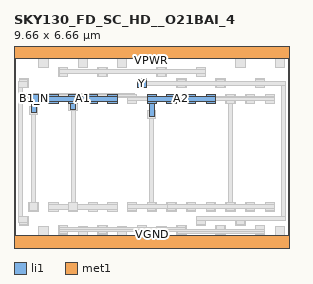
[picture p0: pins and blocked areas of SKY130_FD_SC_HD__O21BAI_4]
MACRO SKY130_FD_SC_HD__O21BAI_4
 CLASS CORE ;
 FOREIGN SKY130_FD_SC_HD__O21BAI_4 0 0 ;
 SIZE 9.66 BY 6.66 ;
 ORIGIN 0 0 ;
 SYMMETRY X Y R90 ;
 SITE unit ;
  PIN VPWR
   DIRECTION INOUT ;
   USE POWER ;
   SHAPE ABUTMENT ;
    PORT
     CLASS CORE ;
       LAYER li1 ;
        RECT 0.00000000 6.42000000 9.66000000 6.90000000 ;
       LAYER met1 ;
        RECT 0.00000000 6.42000000 9.66000000 6.90000000 ;
    END
  END VPWR

  PIN VGND
   DIRECTION INOUT ;
   USE POWER ;
   SHAPE ABUTMENT ;
    PORT
     CLASS CORE ;
       LAYER li1 ;
        RECT 0.00000000 -0.24000000 9.66000000 0.24000000 ;
       LAYER met1 ;
        RECT 0.00000000 -0.24000000 9.66000000 0.24000000 ;
    END
  END VGND

  PIN Y
   DIRECTION INOUT ;
   USE SIGNAL ;
   SHAPE ABUTMENT ;
    PORT
     CLASS CORE ;
       LAYER li1 ;
        RECT 4.32000000 5.40000000 4.65000000 5.73000000 ;
    END
  END Y

  PIN A2
   DIRECTION INOUT ;
   USE SIGNAL ;
   SHAPE ABUTMENT ;
    PORT
     CLASS CORE ;
       LAYER li1 ;
        RECT 4.74500000 4.39200000 4.91500000 4.85200000 ;
        RECT 4.66500000 4.85200000 4.99500000 4.93200000 ;
        RECT 5.35500000 4.85200000 5.68500000 4.93200000 ;
        RECT 6.04500000 4.85200000 6.37500000 4.93200000 ;
        RECT 6.73500000 4.85200000 7.06500000 4.93200000 ;
        RECT 4.66500000 4.93200000 7.06500000 5.10200000 ;
        RECT 4.66500000 5.10200000 4.99500000 5.18200000 ;
        RECT 5.35500000 5.10200000 5.68500000 5.18200000 ;
        RECT 6.04500000 5.10200000 6.37500000 5.18200000 ;
        RECT 6.73500000 5.10200000 7.06500000 5.18200000 ;
    END
  END A2

  PIN A1
   DIRECTION INOUT ;
   USE SIGNAL ;
   SHAPE ABUTMENT ;
    PORT
     CLASS CORE ;
       LAYER li1 ;
        RECT 1.98500000 4.66200000 2.15500000 4.85200000 ;
        RECT 1.21500000 4.85200000 1.54500000 4.93200000 ;
        RECT 1.90500000 4.85200000 2.23500000 4.93200000 ;
        RECT 2.59500000 4.85200000 2.92500000 4.93200000 ;
        RECT 3.28500000 4.85200000 3.61500000 4.93200000 ;
        RECT 1.21500000 4.93200000 3.61500000 5.10200000 ;
        RECT 1.21500000 5.10200000 1.54500000 5.18200000 ;
        RECT 1.90500000 5.10200000 2.23500000 5.18200000 ;
        RECT 2.59500000 5.10200000 2.92500000 5.18200000 ;
        RECT 3.28500000 5.10200000 3.61500000 5.18200000 ;
    END
  END A1

  PIN B1_N
   DIRECTION INOUT ;
   USE SIGNAL ;
   SHAPE ABUTMENT ;
    PORT
     CLASS CORE ;
       LAYER li1 ;
        RECT 0.60500000 4.52700000 0.77500000 4.85200000 ;
        RECT 0.52500000 4.85200000 0.85500000 5.18200000 ;
    END
  END B1_N

 OBS
    LAYER polycont ;
     RECT 0.60500000 1.15200000 0.77500000 1.32200000 ;
     RECT 0.60500000 4.93200000 0.77500000 5.10200000 ;
     RECT 4.05500000 1.15200000 4.22500000 1.32200000 ;
     RECT 4.74500000 1.15200000 4.91500000 1.32200000 ;
     RECT 5.43500000 1.15200000 5.60500000 1.32200000 ;
     RECT 8.88500000 1.15200000 9.05500000 1.32200000 ;
     RECT 4.74500000 4.93200000 4.91500000 5.10200000 ;
     RECT 5.43500000 4.93200000 5.60500000 5.10200000 ;
     RECT 6.12500000 4.93200000 6.29500000 5.10200000 ;
     RECT 6.81500000 4.93200000 6.98500000 5.10200000 ;
     RECT 1.29500000 1.15200000 1.46500000 1.32200000 ;
     RECT 1.98500000 1.15200000 2.15500000 1.32200000 ;
     RECT 2.67500000 1.15200000 2.84500000 1.32200000 ;
     RECT 3.36500000 1.15200000 3.53500000 1.32200000 ;
     RECT 1.29500000 4.93200000 1.46500000 5.10200000 ;
     RECT 1.98500000 4.93200000 2.15500000 5.10200000 ;
     RECT 2.67500000 4.93200000 2.84500000 5.10200000 ;
     RECT 3.36500000 4.93200000 3.53500000 5.10200000 ;
     RECT 6.12500000 1.15200000 6.29500000 1.32200000 ;
     RECT 6.81500000 1.15200000 6.98500000 1.32200000 ;
     RECT 7.50500000 1.15200000 7.67500000 1.32200000 ;
     RECT 8.19500000 1.15200000 8.36500000 1.32200000 ;
     RECT 4.05500000 4.93200000 4.22500000 5.10200000 ;
     RECT 7.50500000 4.93200000 7.67500000 5.10200000 ;
     RECT 8.19500000 4.93200000 8.36500000 5.10200000 ;
     RECT 8.88500000 4.93200000 9.05500000 5.10200000 ;

    LAYER pdiffc ;
     RECT 4.40000000 5.48000000 4.57000000 5.65000000 ;
     RECT 5.78000000 5.48000000 5.95000000 5.65000000 ;
     RECT 7.16000000 5.48000000 7.33000000 5.65000000 ;
     RECT 8.54000000 5.48000000 8.71000000 5.65000000 ;
     RECT 0.95000000 6.19000000 1.12000000 6.36000000 ;
     RECT 2.33000000 6.19000000 2.50000000 6.36000000 ;
     RECT 3.71000000 6.19000000 3.88000000 6.36000000 ;
     RECT 7.85000000 6.19000000 8.02000000 6.36000000 ;
     RECT 9.23000000 6.19000000 9.40000000 6.36000000 ;
     RECT 1.64000000 5.87700000 1.81000000 6.04700000 ;
     RECT 3.02000000 5.87700000 3.19000000 6.04700000 ;
     RECT 5.09000000 5.87700000 5.26000000 6.04700000 ;
     RECT 6.47000000 5.87700000 6.64000000 6.04700000 ;
     RECT 0.26000000 5.48000000 0.43000000 5.65000000 ;

    LAYER ndiffc ;
     RECT 6.47000000 0.66000000 6.64000000 0.83000000 ;
     RECT 7.85000000 0.66000000 8.02000000 0.83000000 ;
     RECT 1.64000000 0.34200000 1.81000000 0.51200000 ;
     RECT 3.02000000 0.34200000 3.19000000 0.51200000 ;
     RECT 4.40000000 0.34200000 4.57000000 0.51200000 ;
     RECT 5.78000000 0.34200000 5.95000000 0.51200000 ;
     RECT 7.16000000 0.34200000 7.33000000 0.51200000 ;
     RECT 8.54000000 0.34200000 8.71000000 0.51200000 ;
     RECT 0.95000000 0.30000000 1.12000000 0.47000000 ;
     RECT 2.33000000 0.30000000 2.50000000 0.47000000 ;
     RECT 3.71000000 0.30000000 3.88000000 0.47000000 ;
     RECT 5.09000000 0.30000000 5.26000000 0.47000000 ;
     RECT 9.23000000 0.30000000 9.40000000 0.47000000 ;
     RECT 0.26000000 0.66000000 0.43000000 0.83000000 ;

    LAYER li1 ;
     RECT 6.39000000 0.58000000 6.72000000 0.91000000 ;
     RECT 7.77000000 0.58000000 8.10000000 0.91000000 ;
     RECT 4.32000000 5.40000000 4.65000000 5.73000000 ;
     RECT 5.70000000 5.40000000 6.03000000 5.73000000 ;
     RECT 7.08000000 5.40000000 7.41000000 5.73000000 ;
     RECT 8.46000000 5.40000000 8.79000000 5.73000000 ;
     RECT 0.52500000 1.07200000 0.85500000 1.40200000 ;
     RECT 0.60500000 4.52700000 0.77500000 4.85200000 ;
     RECT 0.52500000 4.85200000 0.85500000 5.18200000 ;
     RECT 3.97500000 1.07200000 4.30500000 1.40200000 ;
     RECT 4.66500000 1.07200000 4.99500000 1.40200000 ;
     RECT 5.35500000 1.07200000 5.68500000 1.40200000 ;
     RECT 8.80500000 1.07200000 9.13500000 1.40200000 ;
     RECT 4.74500000 4.39200000 4.91500000 4.85200000 ;
     RECT 4.66500000 4.85200000 4.99500000 4.93200000 ;
     RECT 5.35500000 4.85200000 5.68500000 4.93200000 ;
     RECT 6.04500000 4.85200000 6.37500000 4.93200000 ;
     RECT 6.73500000 4.85200000 7.06500000 4.93200000 ;
     RECT 4.66500000 4.93200000 7.06500000 5.10200000 ;
     RECT 4.66500000 5.10200000 4.99500000 5.18200000 ;
     RECT 5.35500000 5.10200000 5.68500000 5.18200000 ;
     RECT 6.04500000 5.10200000 6.37500000 5.18200000 ;
     RECT 6.73500000 5.10200000 7.06500000 5.18200000 ;
     RECT 0.87000000 6.11000000 1.20000000 6.42000000 ;
     RECT 2.25000000 6.11000000 2.58000000 6.42000000 ;
     RECT 3.63000000 6.11000000 3.96000000 6.42000000 ;
     RECT 7.77000000 6.11000000 8.10000000 6.42000000 ;
     RECT 9.15000000 6.11000000 9.48000000 6.42000000 ;
     RECT 0.00000000 6.42000000 9.66000000 6.90000000 ;
     RECT 1.21500000 1.07200000 1.54500000 1.15200000 ;
     RECT 1.90500000 1.07200000 2.23500000 1.15200000 ;
     RECT 2.59500000 1.07200000 2.92500000 1.15200000 ;
     RECT 3.28500000 1.07200000 3.61500000 1.15200000 ;
     RECT 1.21500000 1.15200000 3.61500000 1.32200000 ;
     RECT 1.21500000 1.32200000 1.54500000 1.40200000 ;
     RECT 1.90500000 1.32200000 2.23500000 1.40200000 ;
     RECT 2.59500000 1.32200000 2.92500000 1.40200000 ;
     RECT 3.28500000 1.32200000 3.61500000 1.40200000 ;
     RECT 1.98500000 4.66200000 2.15500000 4.85200000 ;
     RECT 1.21500000 4.85200000 1.54500000 4.93200000 ;
     RECT 1.90500000 4.85200000 2.23500000 4.93200000 ;
     RECT 2.59500000 4.85200000 2.92500000 4.93200000 ;
     RECT 3.28500000 4.85200000 3.61500000 4.93200000 ;
     RECT 1.21500000 4.93200000 3.61500000 5.10200000 ;
     RECT 1.21500000 5.10200000 1.54500000 5.18200000 ;
     RECT 1.90500000 5.10200000 2.23500000 5.18200000 ;
     RECT 2.59500000 5.10200000 2.92500000 5.18200000 ;
     RECT 3.28500000 5.10200000 3.61500000 5.18200000 ;
     RECT 1.56000000 5.79700000 1.89000000 6.12700000 ;
     RECT 2.94000000 5.79700000 3.27000000 6.12700000 ;
     RECT 5.01000000 5.79700000 5.34000000 6.12700000 ;
     RECT 6.39000000 5.79700000 6.72000000 6.12700000 ;
     RECT 1.56000000 0.26200000 1.89000000 0.59200000 ;
     RECT 2.94000000 0.26200000 3.27000000 0.59200000 ;
     RECT 4.32000000 0.26200000 4.65000000 0.59200000 ;
     RECT 5.70000000 0.26200000 6.03000000 0.59200000 ;
     RECT 7.08000000 0.26200000 7.41000000 0.59200000 ;
     RECT 8.46000000 0.26200000 8.79000000 0.59200000 ;
     RECT 0.00000000 -0.24000000 9.66000000 0.24000000 ;
     RECT 0.87000000 0.24000000 1.20000000 0.55000000 ;
     RECT 2.25000000 0.24000000 2.58000000 0.55000000 ;
     RECT 3.63000000 0.24000000 3.96000000 0.55000000 ;
     RECT 5.01000000 0.24000000 5.34000000 0.55000000 ;
     RECT 9.15000000 0.24000000 9.48000000 0.55000000 ;
     RECT 0.18000000 0.58000000 0.51000000 0.91000000 ;
     RECT 6.04500000 1.07200000 6.37500000 1.40200000 ;
     RECT 6.73500000 1.07200000 7.06500000 1.40200000 ;
     RECT 7.42500000 1.07200000 7.75500000 1.40200000 ;
     RECT 8.11500000 1.07200000 8.44500000 1.40200000 ;
     RECT 3.97500000 4.85200000 4.30500000 5.18200000 ;
     RECT 7.42500000 4.85200000 7.75500000 5.18200000 ;
     RECT 8.11500000 4.85200000 8.44500000 5.18200000 ;
     RECT 8.80500000 4.85200000 9.13500000 5.18200000 ;
     RECT 0.18000000 5.40000000 0.51000000 5.73000000 ;

    LAYER viali ;
     RECT 6.47000000 0.66000000 6.64000000 0.83000000 ;
     RECT 7.85000000 0.66000000 8.02000000 0.83000000 ;
     RECT 4.40000000 5.48000000 4.57000000 5.65000000 ;
     RECT 5.78000000 5.48000000 5.95000000 5.65000000 ;
     RECT 7.16000000 5.48000000 7.33000000 5.65000000 ;
     RECT 8.54000000 5.48000000 8.71000000 5.65000000 ;
     RECT 0.60500000 1.15200000 0.77500000 1.32200000 ;
     RECT 0.60500000 4.52700000 0.77500000 4.69700000 ;
     RECT 4.05500000 1.15200000 4.22500000 1.32200000 ;
     RECT 4.74500000 1.15200000 4.91500000 1.32200000 ;
     RECT 5.43500000 1.15200000 5.60500000 1.32200000 ;
     RECT 8.88500000 1.15200000 9.05500000 1.32200000 ;
     RECT 4.74500000 4.39200000 4.91500000 4.56200000 ;
     RECT 9.23000000 6.57500000 9.40000000 6.74500000 ;
     RECT 1.98500000 1.15200000 2.15500000 1.32200000 ;
     RECT 1.98500000 4.66200000 2.15500000 4.83200000 ;
     RECT 1.64000000 5.87700000 1.81000000 6.04700000 ;
     RECT 3.02000000 5.87700000 3.19000000 6.04700000 ;
     RECT 5.09000000 5.87700000 5.26000000 6.04700000 ;
     RECT 6.47000000 5.87700000 6.64000000 6.04700000 ;
     RECT 1.64000000 0.34200000 1.81000000 0.51200000 ;
     RECT 3.02000000 0.34200000 3.19000000 0.51200000 ;
     RECT 4.40000000 0.34200000 4.57000000 0.51200000 ;
     RECT 5.78000000 0.34200000 5.95000000 0.51200000 ;
     RECT 7.16000000 0.34200000 7.33000000 0.51200000 ;
     RECT 8.54000000 0.34200000 8.71000000 0.51200000 ;
     RECT 3.71000000 -0.08500000 3.88000000 0.08500000 ;
     RECT 0.26000000 0.66000000 0.43000000 0.83000000 ;
     RECT 6.12500000 1.15200000 6.29500000 1.32200000 ;
     RECT 6.81500000 1.15200000 6.98500000 1.32200000 ;
     RECT 7.50500000 1.15200000 7.67500000 1.32200000 ;
     RECT 8.19500000 1.15200000 8.36500000 1.32200000 ;
     RECT 4.05500000 4.93200000 4.22500000 5.10200000 ;
     RECT 7.50500000 4.93200000 7.67500000 5.10200000 ;
     RECT 8.19500000 4.93200000 8.36500000 5.10200000 ;
     RECT 8.88500000 4.93200000 9.05500000 5.10200000 ;
     RECT 0.26000000 5.48000000 0.43000000 5.65000000 ;

    LAYER met1 ;
     RECT 6.41000000 0.60000000 6.70000000 0.76200000 ;
     RECT 7.79000000 0.60000000 8.08000000 0.76200000 ;
     RECT 6.41000000 0.76200000 9.50000000 0.89000000 ;
     RECT 6.48500000 0.89000000 9.50000000 0.90200000 ;
     RECT 4.34000000 5.42000000 4.63000000 5.49500000 ;
     RECT 5.72000000 5.42000000 6.01000000 5.49500000 ;
     RECT 7.10000000 5.42000000 7.39000000 5.49500000 ;
     RECT 8.48000000 5.42000000 8.77000000 5.49500000 ;
     RECT 9.36000000 0.90200000 9.50000000 5.49500000 ;
     RECT 4.34000000 5.49500000 9.50000000 5.63500000 ;
     RECT 4.34000000 5.63500000 4.63000000 5.71000000 ;
     RECT 5.72000000 5.63500000 6.01000000 5.71000000 ;
     RECT 7.10000000 5.63500000 7.39000000 5.71000000 ;
     RECT 8.48000000 5.63500000 8.77000000 5.71000000 ;
     RECT 0.54500000 1.09200000 0.83500000 1.38200000 ;
     RECT 0.62000000 1.38200000 0.76000000 4.46700000 ;
     RECT 0.54500000 4.46700000 0.83500000 4.75700000 ;
     RECT 8.82500000 1.09200000 9.11500000 1.38200000 ;
     RECT 3.99500000 1.09200000 4.28500000 1.16700000 ;
     RECT 4.68500000 1.09200000 4.97500000 1.16700000 ;
     RECT 5.37500000 1.09200000 5.66500000 1.16700000 ;
     RECT 3.99500000 1.16700000 5.66500000 1.30700000 ;
     RECT 3.99500000 1.30700000 4.28500000 1.38200000 ;
     RECT 4.68500000 1.30700000 4.97500000 1.38200000 ;
     RECT 5.37500000 1.30700000 5.66500000 1.38200000 ;
     RECT 4.76000000 1.38200000 4.90000000 4.33200000 ;
     RECT 4.68500000 4.33200000 4.97500000 4.62200000 ;
     RECT 0.00000000 6.42000000 9.66000000 6.90000000 ;
     RECT 1.92500000 1.09200000 2.21500000 1.38200000 ;
     RECT 2.00000000 1.38200000 2.14000000 4.60200000 ;
     RECT 1.92500000 4.60200000 2.21500000 4.89200000 ;
     RECT 1.58000000 5.81700000 1.87000000 5.89200000 ;
     RECT 2.96000000 5.81700000 3.25000000 5.89200000 ;
     RECT 5.03000000 5.81700000 5.32000000 5.89200000 ;
     RECT 6.41000000 5.81700000 6.70000000 5.89200000 ;
     RECT 1.58000000 5.89200000 6.70000000 6.03200000 ;
     RECT 1.58000000 6.03200000 1.87000000 6.10700000 ;
     RECT 2.96000000 6.03200000 3.25000000 6.10700000 ;
     RECT 5.03000000 6.03200000 5.32000000 6.10700000 ;
     RECT 6.41000000 6.03200000 6.70000000 6.10700000 ;
     RECT 5.72000000 0.28200000 6.01000000 0.31500000 ;
     RECT 7.10000000 0.28200000 7.39000000 0.31500000 ;
     RECT 8.48000000 0.28200000 8.77000000 0.31500000 ;
     RECT 1.58000000 0.28200000 1.87000000 0.35700000 ;
     RECT 2.96000000 0.28200000 3.25000000 0.35700000 ;
     RECT 4.34000000 0.28200000 4.63000000 0.35700000 ;
     RECT 5.72000000 0.31500000 8.77000000 0.35700000 ;
     RECT 1.58000000 0.35700000 8.77000000 0.45500000 ;
     RECT 1.58000000 0.45500000 6.01000000 0.49700000 ;
     RECT 1.58000000 0.49700000 1.87000000 0.57200000 ;
     RECT 2.96000000 0.49700000 3.25000000 0.57200000 ;
     RECT 4.34000000 0.49700000 4.63000000 0.57200000 ;
     RECT 5.72000000 0.49700000 6.01000000 0.57200000 ;
     RECT 7.10000000 0.45500000 7.39000000 0.57200000 ;
     RECT 8.48000000 0.45500000 8.77000000 0.57200000 ;
     RECT 0.00000000 -0.24000000 9.66000000 0.24000000 ;
     RECT 0.20000000 0.60000000 0.49000000 0.67500000 ;
     RECT 0.16000000 0.67500000 0.49000000 0.89000000 ;
     RECT 6.06500000 1.09200000 6.35500000 1.16700000 ;
     RECT 6.75500000 1.09200000 7.04500000 1.16700000 ;
     RECT 7.44500000 1.09200000 7.73500000 1.16700000 ;
     RECT 8.13500000 1.09200000 8.42500000 1.16700000 ;
     RECT 6.06500000 1.16700000 8.42500000 1.30700000 ;
     RECT 6.06500000 1.30700000 6.35500000 1.38200000 ;
     RECT 6.75500000 1.30700000 7.04500000 1.38200000 ;
     RECT 7.44500000 1.30700000 7.73500000 1.38200000 ;
     RECT 8.13500000 1.30700000 8.42500000 1.38200000 ;
     RECT 7.52000000 1.38200000 7.66000000 4.87200000 ;
     RECT 3.99500000 4.87200000 4.28500000 4.94700000 ;
     RECT 7.44500000 4.87200000 7.73500000 4.94700000 ;
     RECT 8.13500000 4.87200000 8.42500000 4.94700000 ;
     RECT 8.82500000 4.87200000 9.11500000 4.94700000 ;
     RECT 0.16000000 0.89000000 0.30000000 5.08200000 ;
     RECT 3.99500000 4.94700000 9.11500000 5.08200000 ;
     RECT 0.16000000 5.08200000 9.11500000 5.08700000 ;
     RECT 0.16000000 5.08700000 4.28500000 5.16200000 ;
     RECT 7.44500000 5.08700000 7.73500000 5.16200000 ;
     RECT 8.13500000 5.08700000 8.42500000 5.16200000 ;
     RECT 8.82500000 5.08700000 9.11500000 5.16200000 ;
     RECT 0.16000000 5.16200000 4.21000000 5.22200000 ;
     RECT 0.16000000 5.22200000 0.30000000 5.42000000 ;
     RECT 0.16000000 5.42000000 0.49000000 5.63500000 ;
     RECT 0.20000000 5.63500000 0.49000000 5.71000000 ;

    LAYER via ;
     RECT 5.43500000 1.15200000 5.60500000 1.32200000 ;
     RECT 8.88500000 1.15200000 9.05500000 1.32200000 ;

    LAYER met2 ;
     RECT 5.37500000 1.09200000 5.66500000 1.16700000 ;
     RECT 8.82500000 1.09200000 9.11500000 1.16700000 ;
     RECT 5.37500000 1.16700000 9.11500000 1.30700000 ;
     RECT 5.37500000 1.30700000 5.66500000 1.38200000 ;
     RECT 8.82500000 1.30700000 9.11500000 1.38200000 ;

    LAYER via2 ;


    LAYER met3 ;


 END
END SKY130_FD_SC_HD__O21BAI_4
